VERSION 5.7 ;
  NOWIREEXTENSIONATPIN ON ;
  DIVIDERCHAR "/" ;
  BUSBITCHARS "[]" ;
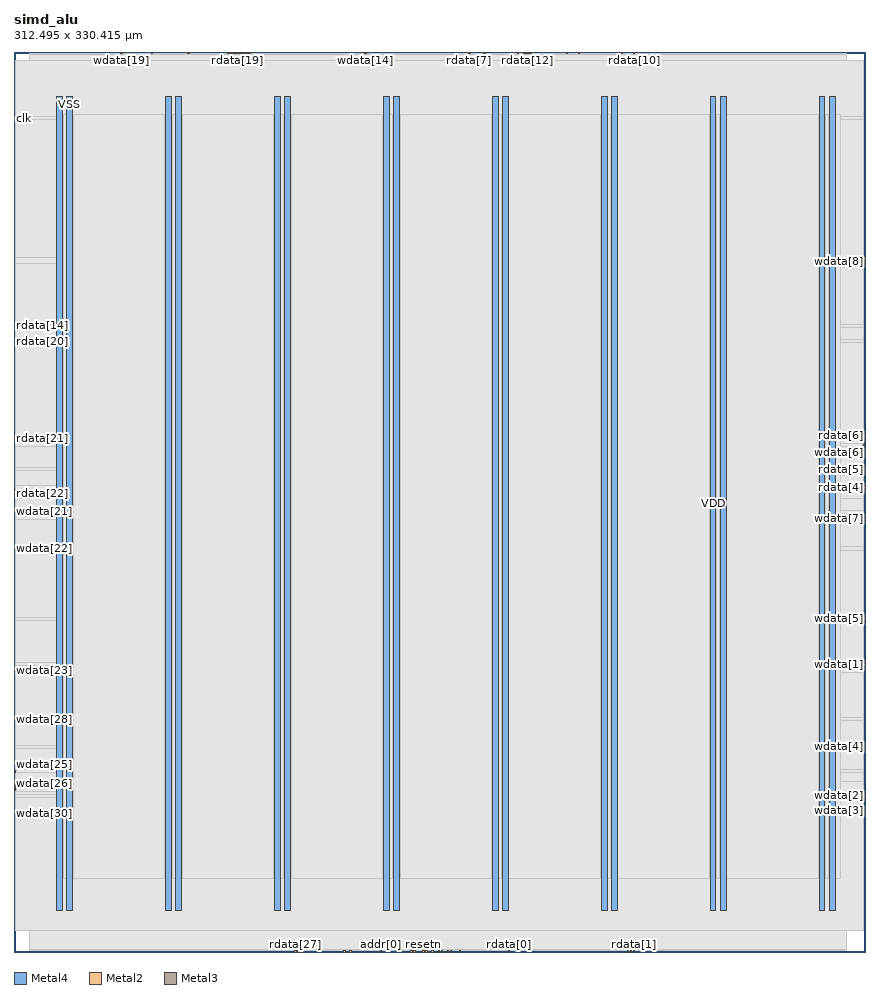
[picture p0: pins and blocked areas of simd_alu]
MACRO simd_alu
  CLASS BLOCK ;
  FOREIGN simd_alu ;
  ORIGIN 0.000 0.000 ;
  SIZE 312.495 BY 330.415 ;
  PIN VDD
    DIRECTION INOUT ;
    USE POWER ;
    PORT
      LAYER Metal4 ;
        RECT 15.720 15.380 17.720 313.900 ;
    END
    PORT
      LAYER Metal4 ;
        RECT 55.720 15.380 57.720 313.900 ;
    END
    PORT
      LAYER Metal4 ;
        RECT 95.720 15.380 97.720 313.900 ;
    END
    PORT
      LAYER Metal4 ;
        RECT 135.720 15.380 137.720 313.900 ;
    END
    PORT
      LAYER Metal4 ;
        RECT 175.720 15.380 177.720 313.900 ;
    END
    PORT
      LAYER Metal4 ;
        RECT 215.720 15.380 217.720 313.900 ;
    END
    PORT
      LAYER Metal4 ;
        RECT 255.720 15.380 257.720 313.900 ;
    END
    PORT
      LAYER Metal4 ;
        RECT 295.720 15.380 297.720 313.900 ;
    END
  END VDD
  PIN VSS
    DIRECTION INOUT ;
    USE GROUND ;
    PORT
      LAYER Metal4 ;
        RECT 19.420 15.380 21.420 313.900 ;
    END
    PORT
      LAYER Metal4 ;
        RECT 59.420 15.380 61.420 313.900 ;
    END
    PORT
      LAYER Metal4 ;
        RECT 99.420 15.380 101.420 313.900 ;
    END
    PORT
      LAYER Metal4 ;
        RECT 139.420 15.380 141.420 313.900 ;
    END
    PORT
      LAYER Metal4 ;
        RECT 179.420 15.380 181.420 313.900 ;
    END
    PORT
      LAYER Metal4 ;
        RECT 219.420 15.380 221.420 313.900 ;
    END
    PORT
      LAYER Metal4 ;
        RECT 259.420 15.380 261.420 313.900 ;
    END
    PORT
      LAYER Metal4 ;
        RECT 299.420 15.380 301.420 313.900 ;
    END
  END VSS
  PIN addr[0]
    DIRECTION INPUT ;
    USE SIGNAL ;
    ANTENNAGATEAREA 0.498500 ;
    PORT
      LAYER Metal2 ;
        RECT 134.400 0.000 134.960 0.560 ;
    END
  END addr[0]
  PIN addr[1]
    DIRECTION INPUT ;
    USE SIGNAL ;
    ANTENNAGATEAREA 0.498500 ;
    PORT
      LAYER Metal2 ;
        RECT 159.040 0.000 159.600 0.560 ;
    END
  END addr[1]
  PIN addr[2]
    DIRECTION INPUT ;
    USE SIGNAL ;
    ANTENNAGATEAREA 0.498500 ;
    PORT
      LAYER Metal2 ;
        RECT 156.800 0.000 157.360 0.560 ;
    END
  END addr[2]
  PIN addr[3]
    DIRECTION INPUT ;
    USE SIGNAL ;
    ANTENNAGATEAREA 0.498500 ;
    PORT
      LAYER Metal2 ;
        RECT 155.680 0.000 156.240 0.560 ;
    END
  END addr[3]
  PIN clk
    DIRECTION INPUT ;
    USE SIGNAL ;
    ANTENNAGATEAREA 4.738000 ;
    PORT
      LAYER Metal3 ;
        RECT 0.000 305.760 0.560 306.320 ;
    END
  END clk
  PIN rdata[0]
    DIRECTION OUTPUT ;
    USE SIGNAL ;
    ANTENNADIFFAREA 1.986000 ;
    PORT
      LAYER Metal2 ;
        RECT 181.440 0.000 182.000 0.560 ;
    END
  END rdata[0]
  PIN rdata[10]
    DIRECTION OUTPUT ;
    USE SIGNAL ;
    ANTENNADIFFAREA 1.986000 ;
    PORT
      LAYER Metal2 ;
        RECT 227.360 329.855 227.920 330.415 ;
    END
  END rdata[10]
  PIN rdata[11]
    DIRECTION OUTPUT ;
    USE SIGNAL ;
    ANTENNADIFFAREA 1.986000 ;
    PORT
      LAYER Metal2 ;
        RECT 207.200 329.855 207.760 330.415 ;
    END
  END rdata[11]
  PIN rdata[12]
    DIRECTION OUTPUT ;
    USE SIGNAL ;
    ANTENNADIFFAREA 1.986000 ;
    PORT
      LAYER Metal2 ;
        RECT 188.160 329.855 188.720 330.415 ;
    END
  END rdata[12]
  PIN rdata[13]
    DIRECTION OUTPUT ;
    USE SIGNAL ;
    ANTENNADIFFAREA 1.986000 ;
    PORT
      LAYER Metal2 ;
        RECT 172.480 329.855 173.040 330.415 ;
    END
  END rdata[13]
  PIN rdata[14]
    DIRECTION OUTPUT ;
    USE SIGNAL ;
    ANTENNADIFFAREA 1.986000 ;
    PORT
      LAYER Metal3 ;
        RECT 0.000 229.600 0.560 230.160 ;
    END
  END rdata[14]
  PIN rdata[15]
    DIRECTION OUTPUT ;
    USE SIGNAL ;
    ANTENNADIFFAREA 1.986000 ;
    PORT
      LAYER Metal2 ;
        RECT 79.520 329.855 80.080 330.415 ;
    END
  END rdata[15]
  PIN rdata[16]
    DIRECTION OUTPUT ;
    USE SIGNAL ;
    ANTENNADIFFAREA 1.986000 ;
    PORT
      LAYER Metal2 ;
        RECT 80.640 329.855 81.200 330.415 ;
    END
  END rdata[16]
  PIN rdata[17]
    DIRECTION OUTPUT ;
    USE SIGNAL ;
    ANTENNADIFFAREA 1.986000 ;
    PORT
      LAYER Metal2 ;
        RECT 85.120 329.855 85.680 330.415 ;
    END
  END rdata[17]
  PIN rdata[18]
    DIRECTION OUTPUT ;
    USE SIGNAL ;
    ANTENNADIFFAREA 1.986000 ;
    PORT
      LAYER Metal2 ;
        RECT 84.000 329.855 84.560 330.415 ;
    END
  END rdata[18]
  PIN rdata[19]
    DIRECTION OUTPUT ;
    USE SIGNAL ;
    ANTENNADIFFAREA 1.986000 ;
    PORT
      LAYER Metal2 ;
        RECT 81.760 329.855 82.320 330.415 ;
    END
  END rdata[19]
  PIN rdata[1]
    DIRECTION OUTPUT ;
    USE SIGNAL ;
    ANTENNADIFFAREA 1.986000 ;
    PORT
      LAYER Metal2 ;
        RECT 227.360 0.000 227.920 0.560 ;
    END
  END rdata[1]
  PIN rdata[20]
    DIRECTION OUTPUT ;
    USE SIGNAL ;
    ANTENNADIFFAREA 1.986000 ;
    PORT
      LAYER Metal3 ;
        RECT 0.000 224.000 0.560 224.560 ;
    END
  END rdata[20]
  PIN rdata[21]
    DIRECTION OUTPUT ;
    USE SIGNAL ;
    ANTENNADIFFAREA 1.986000 ;
    PORT
      LAYER Metal3 ;
        RECT 0.000 188.160 0.560 188.720 ;
    END
  END rdata[21]
  PIN rdata[22]
    DIRECTION OUTPUT ;
    USE SIGNAL ;
    ANTENNADIFFAREA 1.986000 ;
    PORT
      LAYER Metal3 ;
        RECT 0.000 168.000 0.560 168.560 ;
    END
  END rdata[22]
  PIN rdata[23]
    DIRECTION OUTPUT ;
    USE SIGNAL ;
    ANTENNADIFFAREA 1.986000 ;
    PORT
      LAYER Metal3 ;
        RECT 0.000 169.120 0.560 169.680 ;
    END
  END rdata[23]
  PIN rdata[24]
    DIRECTION OUTPUT ;
    USE SIGNAL ;
    ANTENNADIFFAREA 1.986000 ;
    PORT
      LAYER Metal2 ;
        RECT 123.200 0.000 123.760 0.560 ;
    END
  END rdata[24]
  PIN rdata[25]
    DIRECTION OUTPUT ;
    USE SIGNAL ;
    ANTENNADIFFAREA 1.986000 ;
    PORT
      LAYER Metal2 ;
        RECT 153.440 0.000 154.000 0.560 ;
    END
  END rdata[25]
  PIN rdata[26]
    DIRECTION OUTPUT ;
    USE SIGNAL ;
    ANTENNADIFFAREA 1.986000 ;
    PORT
      LAYER Metal2 ;
        RECT 120.960 0.000 121.520 0.560 ;
    END
  END rdata[26]
  PIN rdata[27]
    DIRECTION OUTPUT ;
    USE SIGNAL ;
    ANTENNADIFFAREA 1.986000 ;
    PORT
      LAYER Metal2 ;
        RECT 103.040 0.000 103.600 0.560 ;
    END
  END rdata[27]
  PIN rdata[28]
    DIRECTION OUTPUT ;
    USE SIGNAL ;
    ANTENNADIFFAREA 1.986000 ;
    PORT
      LAYER Metal2 ;
        RECT 104.160 0.000 104.720 0.560 ;
    END
  END rdata[28]
  PIN rdata[29]
    DIRECTION OUTPUT ;
    USE SIGNAL ;
    ANTENNADIFFAREA 1.986000 ;
    PORT
      LAYER Metal2 ;
        RECT 105.280 0.000 105.840 0.560 ;
    END
  END rdata[29]
  PIN rdata[2]
    DIRECTION OUTPUT ;
    USE SIGNAL ;
    ANTENNADIFFAREA 1.986000 ;
    PORT
      LAYER Metal2 ;
        RECT 226.240 0.000 226.800 0.560 ;
    END
  END rdata[2]
  PIN rdata[30]
    DIRECTION OUTPUT ;
    USE SIGNAL ;
    ANTENNADIFFAREA 1.986000 ;
    PORT
      LAYER Metal2 ;
        RECT 145.600 0.000 146.160 0.560 ;
    END
  END rdata[30]
  PIN rdata[31]
    DIRECTION OUTPUT ;
    USE SIGNAL ;
    ANTENNADIFFAREA 1.986000 ;
    PORT
      LAYER Metal2 ;
        RECT 151.200 0.000 151.760 0.560 ;
    END
  END rdata[31]
  PIN rdata[3]
    DIRECTION OUTPUT ;
    USE SIGNAL ;
    ANTENNADIFFAREA 1.986000 ;
    PORT
      LAYER Metal2 ;
        RECT 225.120 0.000 225.680 0.560 ;
    END
  END rdata[3]
  PIN rdata[4]
    DIRECTION OUTPUT ;
    USE SIGNAL ;
    ANTENNADIFFAREA 1.986000 ;
    PORT
      LAYER Metal3 ;
        RECT 311.935 170.240 312.495 170.800 ;
    END
  END rdata[4]
  PIN rdata[5]
    DIRECTION OUTPUT ;
    USE SIGNAL ;
    ANTENNADIFFAREA 1.986000 ;
    PORT
      LAYER Metal3 ;
        RECT 311.935 176.960 312.495 177.520 ;
    END
  END rdata[5]
  PIN rdata[6]
    DIRECTION OUTPUT ;
    USE SIGNAL ;
    ANTENNADIFFAREA 1.986000 ;
    PORT
      LAYER Metal3 ;
        RECT 311.935 189.280 312.495 189.840 ;
    END
  END rdata[6]
  PIN rdata[7]
    DIRECTION OUTPUT ;
    USE SIGNAL ;
    ANTENNADIFFAREA 1.986000 ;
    PORT
      LAYER Metal2 ;
        RECT 166.880 329.855 167.440 330.415 ;
    END
  END rdata[7]
  PIN rdata[8]
    DIRECTION OUTPUT ;
    USE SIGNAL ;
    ANTENNADIFFAREA 1.986000 ;
    PORT
      LAYER Metal2 ;
        RECT 187.040 329.855 187.600 330.415 ;
    END
  END rdata[8]
  PIN rdata[9]
    DIRECTION OUTPUT ;
    USE SIGNAL ;
    ANTENNADIFFAREA 1.986000 ;
    PORT
      LAYER Metal2 ;
        RECT 222.880 329.855 223.440 330.415 ;
    END
  END rdata[9]
  PIN resetn
    DIRECTION INPUT ;
    USE SIGNAL ;
    ANTENNAGATEAREA 0.498500 ;
    PORT
      LAYER Metal2 ;
        RECT 150.080 0.000 150.640 0.560 ;
    END
  END resetn
  PIN wdata[0]
    DIRECTION INPUT ;
    USE SIGNAL ;
    ANTENNAGATEAREA 0.498500 ;
    PORT
      LAYER Metal2 ;
        RECT 163.520 0.000 164.080 0.560 ;
    END
  END wdata[0]
  PIN wdata[10]
    DIRECTION INPUT ;
    USE SIGNAL ;
    ANTENNAGATEAREA 0.498500 ;
    PORT
      LAYER Metal2 ;
        RECT 202.720 329.855 203.280 330.415 ;
    END
  END wdata[10]
  PIN wdata[11]
    DIRECTION INPUT ;
    USE SIGNAL ;
    ANTENNAGATEAREA 0.498500 ;
    PORT
      LAYER Metal2 ;
        RECT 189.280 329.855 189.840 330.415 ;
    END
  END wdata[11]
  PIN wdata[12]
    DIRECTION INPUT ;
    USE SIGNAL ;
    ANTENNAGATEAREA 0.498500 ;
    PORT
      LAYER Metal2 ;
        RECT 184.800 329.855 185.360 330.415 ;
    END
  END wdata[12]
  PIN wdata[13]
    DIRECTION INPUT ;
    USE SIGNAL ;
    ANTENNAGATEAREA 0.498500 ;
    PORT
      LAYER Metal2 ;
        RECT 82.880 329.855 83.440 330.415 ;
    END
  END wdata[13]
  PIN wdata[14]
    DIRECTION INPUT ;
    USE SIGNAL ;
    ANTENNAGATEAREA 0.498500 ;
    PORT
      LAYER Metal2 ;
        RECT 128.800 329.855 129.360 330.415 ;
    END
  END wdata[14]
  PIN wdata[15]
    DIRECTION INPUT ;
    USE SIGNAL ;
    ANTENNAGATEAREA 0.498500 ;
    PORT
      LAYER Metal2 ;
        RECT 86.240 329.855 86.800 330.415 ;
    END
  END wdata[15]
  PIN wdata[16]
    DIRECTION INPUT ;
    USE SIGNAL ;
    ANTENNAGATEAREA 0.498500 ;
    PORT
      LAYER Metal2 ;
        RECT 78.400 329.855 78.960 330.415 ;
    END
  END wdata[16]
  PIN wdata[17]
    DIRECTION INPUT ;
    USE SIGNAL ;
    ANTENNAGATEAREA 0.498500 ;
    PORT
      LAYER Metal2 ;
        RECT 63.840 329.855 64.400 330.415 ;
    END
  END wdata[17]
  PIN wdata[18]
    DIRECTION INPUT ;
    USE SIGNAL ;
    ANTENNAGATEAREA 0.498500 ;
    PORT
      LAYER Metal2 ;
        RECT 50.400 329.855 50.960 330.415 ;
    END
  END wdata[18]
  PIN wdata[19]
    DIRECTION INPUT ;
    USE SIGNAL ;
    ANTENNAGATEAREA 0.498500 ;
    PORT
      LAYER Metal2 ;
        RECT 39.200 329.855 39.760 330.415 ;
    END
  END wdata[19]
  PIN wdata[1]
    DIRECTION INPUT ;
    USE SIGNAL ;
    ANTENNAGATEAREA 0.498500 ;
    PORT
      LAYER Metal3 ;
        RECT 311.935 105.280 312.495 105.840 ;
    END
  END wdata[1]
  PIN wdata[20]
    DIRECTION INPUT ;
    USE SIGNAL ;
    ANTENNAGATEAREA 0.498500 ;
    PORT
      LAYER Metal3 ;
        RECT 0.000 166.880 0.560 167.440 ;
    END
  END wdata[20]
  PIN wdata[21]
    DIRECTION INPUT ;
    USE SIGNAL ;
    ANTENNAGATEAREA 0.498500 ;
    PORT
      LAYER Metal3 ;
        RECT 0.000 161.280 0.560 161.840 ;
    END
  END wdata[21]
  PIN wdata[22]
    DIRECTION INPUT ;
    USE SIGNAL ;
    ANTENNAGATEAREA 0.498500 ;
    PORT
      LAYER Metal3 ;
        RECT 0.000 147.840 0.560 148.400 ;
    END
  END wdata[22]
  PIN wdata[23]
    DIRECTION INPUT ;
    USE SIGNAL ;
    ANTENNAGATEAREA 0.498500 ;
    PORT
      LAYER Metal3 ;
        RECT 0.000 103.040 0.560 103.600 ;
    END
  END wdata[23]
  PIN wdata[24]
    DIRECTION INPUT ;
    USE SIGNAL ;
    ANTENNAGATEAREA 0.498500 ;
    PORT
      LAYER Metal3 ;
        RECT 0.000 104.160 0.560 104.720 ;
    END
  END wdata[24]
  PIN wdata[25]
    DIRECTION INPUT ;
    USE SIGNAL ;
    ANTENNAGATEAREA 0.498500 ;
    PORT
      LAYER Metal3 ;
        RECT 0.000 66.080 0.560 66.640 ;
    END
  END wdata[25]
  PIN wdata[26]
    DIRECTION INPUT ;
    USE SIGNAL ;
    ANTENNAGATEAREA 0.498500 ;
    PORT
      LAYER Metal3 ;
        RECT 0.000 61.600 0.560 62.160 ;
    END
  END wdata[26]
  PIN wdata[27]
    DIRECTION INPUT ;
    USE SIGNAL ;
    ANTENNAGATEAREA 0.498500 ;
    PORT
      LAYER Metal3 ;
        RECT 0.000 60.480 0.560 61.040 ;
    END
  END wdata[27]
  PIN wdata[28]
    DIRECTION INPUT ;
    USE SIGNAL ;
    ANTENNAGATEAREA 0.498500 ;
    PORT
      LAYER Metal3 ;
        RECT 0.000 85.120 0.560 85.680 ;
    END
  END wdata[28]
  PIN wdata[29]
    DIRECTION INPUT ;
    USE SIGNAL ;
    ANTENNAGATEAREA 0.498500 ;
    PORT
      LAYER Metal3 ;
        RECT 0.000 59.360 0.560 59.920 ;
    END
  END wdata[29]
  PIN wdata[2]
    DIRECTION INPUT ;
    USE SIGNAL ;
    ANTENNAGATEAREA 0.498500 ;
    PORT
      LAYER Metal3 ;
        RECT 311.935 57.120 312.495 57.680 ;
    END
  END wdata[2]
  PIN wdata[30]
    DIRECTION INPUT ;
    USE SIGNAL ;
    ANTENNAGATEAREA 0.498500 ;
    PORT
      LAYER Metal3 ;
        RECT 0.000 50.400 0.560 50.960 ;
    END
  END wdata[30]
  PIN wdata[31]
    DIRECTION INPUT ;
    USE SIGNAL ;
    ANTENNAGATEAREA 0.498500 ;
    PORT
      LAYER Metal2 ;
        RECT 146.720 0.000 147.280 0.560 ;
    END
  END wdata[31]
  PIN wdata[3]
    DIRECTION INPUT ;
    USE SIGNAL ;
    ANTENNAGATEAREA 0.498500 ;
    PORT
      LAYER Metal3 ;
        RECT 311.935 51.520 312.495 52.080 ;
    END
  END wdata[3]
  PIN wdata[4]
    DIRECTION INPUT ;
    USE SIGNAL ;
    ANTENNAGATEAREA 0.498500 ;
    PORT
      LAYER Metal3 ;
        RECT 311.935 75.040 312.495 75.600 ;
    END
  END wdata[4]
  PIN wdata[5]
    DIRECTION INPUT ;
    USE SIGNAL ;
    ANTENNAGATEAREA 0.498500 ;
    PORT
      LAYER Metal3 ;
        RECT 311.935 122.080 312.495 122.640 ;
    END
  END wdata[5]
  PIN wdata[6]
    DIRECTION INPUT ;
    USE SIGNAL ;
    ANTENNAGATEAREA 0.498500 ;
    PORT
      LAYER Metal3 ;
        RECT 311.935 185.920 312.495 186.480 ;
    END
  END wdata[6]
  PIN wdata[7]
    DIRECTION INPUT ;
    USE SIGNAL ;
    ANTENNAGATEAREA 0.498500 ;
    PORT
      LAYER Metal3 ;
        RECT 311.935 159.040 312.495 159.600 ;
    END
  END wdata[7]
  PIN wdata[8]
    DIRECTION INPUT ;
    USE SIGNAL ;
    ANTENNAGATEAREA 0.498500 ;
    PORT
      LAYER Metal3 ;
        RECT 311.935 253.120 312.495 253.680 ;
    END
  END wdata[8]
  PIN wdata[9]
    DIRECTION INPUT ;
    USE SIGNAL ;
    ANTENNAGATEAREA 0.498500 ;
    PORT
      LAYER Metal3 ;
        RECT 311.935 254.240 312.495 254.800 ;
    END
  END wdata[9]
  PIN wr
    DIRECTION INPUT ;
    USE SIGNAL ;
    ANTENNAGATEAREA 0.498500 ;
    PORT
      LAYER Metal2 ;
        RECT 160.160 0.000 160.720 0.560 ;
    END
  END wr
  OBS
      LAYER Nwell ;
        RECT 6.290 15.250 306.190 314.030 ;
      LAYER Metal1 ;
        RECT 6.720 15.380 305.760 313.900 ;
      LAYER Metal2 ;
        RECT 5.740 329.555 38.900 329.855 ;
        RECT 40.060 329.555 50.100 329.855 ;
        RECT 51.260 329.555 63.540 329.855 ;
        RECT 64.700 329.555 78.100 329.855 ;
        RECT 87.100 329.555 128.500 329.855 ;
        RECT 129.660 329.555 166.580 329.855 ;
        RECT 167.740 329.555 172.180 329.855 ;
        RECT 173.340 329.555 184.500 329.855 ;
        RECT 185.660 329.555 186.740 329.855 ;
        RECT 190.140 329.555 202.420 329.855 ;
        RECT 203.580 329.555 206.900 329.855 ;
        RECT 208.060 329.555 222.580 329.855 ;
        RECT 223.740 329.555 227.060 329.855 ;
        RECT 228.220 329.555 305.620 329.855 ;
        RECT 5.740 0.860 305.620 329.555 ;
        RECT 5.740 0.560 102.740 0.860 ;
        RECT 106.140 0.560 120.660 0.860 ;
        RECT 121.820 0.560 122.900 0.860 ;
        RECT 124.060 0.560 134.100 0.860 ;
        RECT 135.260 0.560 145.300 0.860 ;
        RECT 147.580 0.560 149.780 0.860 ;
        RECT 152.060 0.560 153.140 0.860 ;
        RECT 154.300 0.560 155.380 0.860 ;
        RECT 157.660 0.560 158.740 0.860 ;
        RECT 161.020 0.560 163.220 0.860 ;
        RECT 164.380 0.560 181.140 0.860 ;
        RECT 182.300 0.560 224.820 0.860 ;
        RECT 228.220 0.560 305.620 0.860 ;
      LAYER Metal3 ;
        RECT 0.560 306.620 311.935 327.460 ;
        RECT 0.860 305.460 311.935 306.620 ;
        RECT 0.560 255.100 311.935 305.460 ;
        RECT 0.560 252.820 311.635 255.100 ;
        RECT 0.560 230.460 311.935 252.820 ;
        RECT 0.860 229.300 311.935 230.460 ;
        RECT 0.560 224.860 311.935 229.300 ;
        RECT 0.860 223.700 311.935 224.860 ;
        RECT 0.560 190.140 311.935 223.700 ;
        RECT 0.560 189.020 311.635 190.140 ;
        RECT 0.860 188.980 311.635 189.020 ;
        RECT 0.860 187.860 311.935 188.980 ;
        RECT 0.560 186.780 311.935 187.860 ;
        RECT 0.560 185.620 311.635 186.780 ;
        RECT 0.560 177.820 311.935 185.620 ;
        RECT 0.560 176.660 311.635 177.820 ;
        RECT 0.560 171.100 311.935 176.660 ;
        RECT 0.560 169.980 311.635 171.100 ;
        RECT 0.860 169.940 311.635 169.980 ;
        RECT 0.860 166.580 311.935 169.940 ;
        RECT 0.560 162.140 311.935 166.580 ;
        RECT 0.860 160.980 311.935 162.140 ;
        RECT 0.560 159.900 311.935 160.980 ;
        RECT 0.560 158.740 311.635 159.900 ;
        RECT 0.560 148.700 311.935 158.740 ;
        RECT 0.860 147.540 311.935 148.700 ;
        RECT 0.560 122.940 311.935 147.540 ;
        RECT 0.560 121.780 311.635 122.940 ;
        RECT 0.560 106.140 311.935 121.780 ;
        RECT 0.560 105.020 311.635 106.140 ;
        RECT 0.860 104.980 311.635 105.020 ;
        RECT 0.860 102.740 311.935 104.980 ;
        RECT 0.560 85.980 311.935 102.740 ;
        RECT 0.860 84.820 311.935 85.980 ;
        RECT 0.560 75.900 311.935 84.820 ;
        RECT 0.560 74.740 311.635 75.900 ;
        RECT 0.560 66.940 311.935 74.740 ;
        RECT 0.860 65.780 311.935 66.940 ;
        RECT 0.560 62.460 311.935 65.780 ;
        RECT 0.860 59.060 311.935 62.460 ;
        RECT 0.560 57.980 311.935 59.060 ;
        RECT 0.560 56.820 311.635 57.980 ;
        RECT 0.560 52.380 311.935 56.820 ;
        RECT 0.560 51.260 311.635 52.380 ;
        RECT 0.860 51.220 311.635 51.260 ;
        RECT 0.860 50.100 311.935 51.220 ;
        RECT 0.560 7.980 311.935 50.100 ;
      LAYER Metal4 ;
        RECT 18.060 26.970 19.120 307.350 ;
        RECT 21.720 26.970 55.420 307.350 ;
        RECT 58.020 26.970 59.120 307.350 ;
        RECT 61.720 26.970 95.420 307.350 ;
        RECT 98.020 26.970 99.120 307.350 ;
        RECT 101.720 26.970 135.420 307.350 ;
        RECT 138.020 26.970 139.120 307.350 ;
        RECT 141.720 26.970 175.420 307.350 ;
        RECT 178.020 26.970 179.120 307.350 ;
        RECT 181.720 26.970 215.420 307.350 ;
        RECT 218.020 26.970 219.120 307.350 ;
        RECT 221.720 26.970 255.420 307.350 ;
        RECT 258.020 26.970 259.120 307.350 ;
        RECT 261.720 26.970 295.420 307.350 ;
        RECT 298.020 26.970 299.120 307.350 ;
        RECT 301.720 26.970 303.380 307.350 ;
  END
END simd_alu
END LIBRARY

